VERSION 5.8 ;
BUSBITCHARS "[]" ;
DIVIDERCHAR "/" ;
UNITS
    DATABASE MICRONS 1000 ;
END UNITS

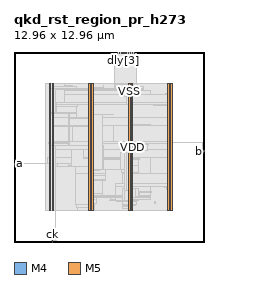
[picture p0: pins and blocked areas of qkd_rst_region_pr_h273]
MACRO qkd_rst_region_pr_h273
  FOREIGN qkd_rst_region_pr_h273 0 0 ;
  CLASS BLOCK ;
  SIZE 12.96 BY 12.96 ;
  PIN a
    DIRECTION INPUT ;
    USE SIGNAL ;
    PORT
      LAYER M4 ;
        RECT  0 5.328 0.084 5.352 ;
    END
  END a
  PIN b
    DIRECTION OUTPUT ;
    USE SIGNAL ;
    PORT
      LAYER M4 ;
        RECT  12.876 6.192 12.96 6.216 ;
    END
  END b
  PIN ck
    DIRECTION INPUT ;
    USE SIGNAL ;
    PORT
      LAYER M5 ;
        RECT  2.592 0 2.616 0.084 ;
    END
  END ck
  PIN dly[0]
    DIRECTION INPUT ;
    USE SIGNAL ;
    PORT
      LAYER M5 ;
        RECT  7.056 12.876 7.08 12.96 ;
    END
  END dly[0]
  PIN dly[1]
    DIRECTION INPUT ;
    USE SIGNAL ;
    PORT
      LAYER M5 ;
        RECT  7.2 12.876 7.224 12.96 ;
    END
  END dly[1]
  PIN dly[2]
    DIRECTION INPUT ;
    USE SIGNAL ;
    PORT
      LAYER M5 ;
        RECT  7.344 12.876 7.368 12.96 ;
    END
  END dly[2]
  PIN dly[3]
    DIRECTION INPUT ;
    USE SIGNAL ;
    PORT
      LAYER M5 ;
        RECT  7.488 12.876 7.512 12.96 ;
    END
  END dly[3]
  PIN dly[4]
    DIRECTION INPUT ;
    USE SIGNAL ;
    PORT
      LAYER M5 ;
        RECT  7.632 12.876 7.656 12.96 ;
    END
  END dly[4]
  PIN dly[5]
    DIRECTION INPUT ;
    USE SIGNAL ;
    PORT
      LAYER M5 ;
        RECT  7.776 12.876 7.8 12.96 ;
    END
  END dly[5]
  PIN dly[6]
    DIRECTION INPUT ;
    USE SIGNAL ;
    PORT
      LAYER M5 ;
        RECT  7.92 12.876 7.944 12.96 ;
    END
  END dly[6]
  PIN dly[7]
    DIRECTION INPUT ;
    USE SIGNAL ;
    PORT
      LAYER M5 ;
        RECT  8.064 12.876 8.088 12.96 ;
    END
  END dly[7]
  PIN por_n
    DIRECTION INPUT ;
    USE SIGNAL ;
    PORT
      LAYER M5 ;
        RECT  8.208 12.876 8.232 12.96 ;
    END
  END por_n
  PIN VDD
    DIRECTION INOUT ;
    USE POWER ;
    PORT
      LAYER M5 ;
        RECT  10.692 2.151 10.812 10.809 ;
        RECT  7.992 2.151 8.112 10.809 ;
        RECT  5.292 2.151 5.412 10.809 ;
        RECT  2.592 2.151 2.712 10.809 ;
    END
  END VDD
  PIN VSS
    DIRECTION INOUT ;
    USE GROUND ;
    PORT
      LAYER M5 ;
        RECT  10.5 2.137 10.62 10.823 ;
        RECT  7.8 2.137 7.92 10.823 ;
        RECT  5.1 2.137 5.22 10.823 ;
        RECT  2.4 2.137 2.52 10.823 ;
    END
  END VSS
  OBS
    LAYER RVTN ;
     RECT  2.16 2.16 10.8 2.295 ;
     RECT  2.16 2.565 10.8 2.835 ;
     RECT  2.16 3.105 10.8 3.375 ;
     RECT  2.16 3.645 10.8 3.915 ;
     RECT  2.16 4.185 10.8 4.455 ;
     RECT  2.16 4.725 10.8 4.995 ;
     RECT  2.16 5.265 10.8 5.535 ;
     RECT  2.16 5.805 10.8 6.075 ;
     RECT  2.16 6.345 10.8 6.615 ;
     RECT  2.16 6.885 10.8 7.155 ;
     RECT  2.16 7.425 10.8 7.695 ;
     RECT  2.16 7.965 10.8 8.235 ;
     RECT  2.16 8.505 10.8 8.775 ;
     RECT  2.16 9.045 10.8 9.315 ;
     RECT  2.16 9.585 10.8 9.855 ;
     RECT  2.16 10.125 10.8 10.395 ;
     RECT  2.16 10.665 10.8 10.8 ;
    LAYER RVTP ;
     RECT  2.16 2.295 10.8 2.565 ;
     RECT  2.16 2.835 10.8 3.105 ;
     RECT  2.16 3.375 10.8 3.645 ;
     RECT  2.16 3.915 10.8 4.185 ;
     RECT  2.16 4.455 10.8 4.725 ;
     RECT  2.16 4.995 10.8 5.265 ;
     RECT  2.16 5.535 10.8 5.805 ;
     RECT  2.16 6.075 10.8 6.345 ;
     RECT  2.16 6.615 10.8 6.885 ;
     RECT  2.16 7.155 10.8 7.425 ;
     RECT  2.16 7.695 10.8 7.965 ;
     RECT  2.16 8.235 10.8 8.505 ;
     RECT  2.16 8.775 10.8 9.045 ;
     RECT  2.16 9.315 10.8 9.585 ;
     RECT  2.16 9.855 10.8 10.125 ;
     RECT  2.16 10.395 10.8 10.665 ;
    LAYER M1 ;
     RECT  2.16 2.151 10.8 10.809 ;
    LAYER M2 ;
     RECT  2.16 2.151 10.8 10.809 ;
     RECT  10.8 2.421 10.812 10.539 ;
     RECT  10.812 6.786 12.875 6.804 ;
    LAYER M3 ;
     RECT  5.115 2.143 5.205 2.191 ;
     RECT  7.815 2.143 7.905 2.299 ;
     RECT  4.32 2.191 4.338 2.335 ;
     RECT  5.115 2.191 5.49 2.335 ;
     RECT  2.415 2.143 2.505 2.413 ;
     RECT  7.416 2.299 7.905 2.413 ;
     RECT  10.515 2.143 10.605 2.413 ;
     RECT  7.416 2.413 8.097 2.461 ;
     RECT  7.416 2.461 8.298 2.569 ;
     RECT  4.284 2.335 5.49 2.621 ;
     RECT  4.32 2.621 5.49 2.641 ;
     RECT  7.416 2.569 8.334 2.731 ;
     RECT  9.612 2.641 9.63 2.759 ;
     RECT  7.02 2.731 8.334 2.803 ;
     RECT  6.552 2.803 8.334 2.839 ;
     RECT  6.552 2.839 8.478 2.875 ;
     RECT  4.32 2.641 5.598 3.037 ;
     RECT  6.552 2.875 9.342 3.037 ;
     RECT  4.32 3.037 9.342 3.137 ;
     RECT  4.788 3.137 9.342 3.173 ;
     RECT  4.788 3.173 6.066 3.335 ;
     RECT  10.515 2.413 10.797 3.577 ;
     RECT  10.368 3.577 10.797 3.685 ;
     RECT  6.948 3.173 9.342 3.811 ;
     RECT  10.26 3.685 10.797 3.811 ;
     RECT  6.948 3.811 10.797 3.983 ;
     RECT  5.076 3.335 6.066 4.225 ;
     RECT  5.076 4.225 6.21 4.261 ;
     RECT  5.076 4.261 6.246 4.531 ;
     RECT  7.416 3.983 10.797 4.649 ;
     RECT  4.572 4.531 6.246 4.651 ;
     RECT  7.416 4.649 8.514 4.765 ;
     RECT  4.356 4.651 6.246 4.955 ;
     RECT  2.415 2.413 2.697 5.131 ;
     RECT  4.356 4.955 4.374 5.165 ;
     RECT  5.115 4.955 6.246 5.233 ;
     RECT  7.308 4.765 8.514 5.233 ;
     RECT  2.415 5.131 2.97 5.323 ;
     RECT  2.304 5.323 2.97 5.341 ;
     RECT  3.744 5.197 3.942 5.341 ;
     RECT  5.115 5.233 8.514 5.611 ;
     RECT  5.115 5.611 8.586 5.701 ;
     RECT  2.304 5.341 3.942 5.765 ;
     RECT  4.716 5.701 8.586 5.773 ;
     RECT  9.324 4.649 10.797 5.773 ;
     RECT  2.415 5.765 3.942 6.313 ;
     RECT  4.716 5.773 10.797 6.313 ;
     RECT  2.415 6.313 10.797 6.691 ;
     RECT  2.376 6.691 10.797 6.749 ;
     RECT  2.376 6.749 4.158 6.809 ;
     RECT  12.852 6.187 12.87 6.809 ;
     RECT  2.415 6.809 4.158 6.845 ;
     RECT  4.932 6.749 10.797 6.845 ;
     RECT  4.932 6.845 6.03 6.881 ;
     RECT  2.415 6.845 3.978 7.861 ;
     RECT  5.115 6.881 6.03 7.861 ;
     RECT  2.415 7.861 6.03 7.933 ;
     RECT  6.768 6.845 10.797 7.933 ;
     RECT  2.415 7.933 10.797 8.501 ;
     RECT  2.415 8.501 4.266 8.779 ;
     RECT  2.412 8.779 4.266 8.843 ;
     RECT  2.415 8.843 4.266 9.247 ;
     RECT  2.415 9.247 4.338 9.355 ;
     RECT  5.115 8.501 10.797 9.355 ;
     RECT  2.415 9.355 10.797 9.509 ;
     RECT  3.42 9.509 10.797 10.049 ;
     RECT  3.42 10.049 9.378 10.085 ;
     RECT  10.224 10.049 10.797 10.085 ;
     RECT  10.332 10.085 10.797 10.121 ;
     RECT  3.42 10.085 9.306 10.319 ;
     RECT  2.415 9.509 2.697 10.411 ;
     RECT  3.42 10.319 8.802 10.411 ;
     RECT  2.415 10.411 8.802 10.463 ;
     RECT  5.115 10.463 6.102 10.547 ;
     RECT  10.515 10.121 10.797 10.547 ;
     RECT  2.415 10.463 4.23 10.589 ;
     RECT  6.84 10.463 8.802 10.589 ;
     RECT  2.415 10.589 4.014 10.625 ;
     RECT  3.42 10.625 4.014 10.661 ;
     RECT  6.084 10.547 6.102 10.661 ;
     RECT  3.42 10.661 3.438 10.769 ;
     RECT  6.84 10.589 6.858 10.781 ;
     RECT  7.632 10.589 8.37 10.781 ;
     RECT  2.415 10.625 2.505 10.817 ;
     RECT  5.115 10.547 5.205 10.817 ;
     RECT  7.815 10.781 8.37 10.817 ;
     RECT  10.515 10.547 10.605 10.817 ;
     RECT  8.352 10.817 8.37 10.829 ;
    LAYER M4 ;
     RECT  0.06 5.328 2.408 5.352 ;
     RECT  2.401 8.784 2.408 8.808 ;
     RECT  2.408 2.148 2.512 10.812 ;
     RECT  2.512 2.418 2.704 10.542 ;
     RECT  2.581 0.096 2.867 0.12 ;
     RECT  2.704 8.784 2.867 9.432 ;
     RECT  2.704 10.416 3.089 10.44 ;
     RECT  2.867 8.784 3.692 8.808 ;
     RECT  2.704 6.576 3.697 6.696 ;
     RECT  3.697 6.576 3.733 6.744 ;
     RECT  3.692 8.16 3.779 8.808 ;
     RECT  2.704 5.136 4.165 5.16 ;
     RECT  4.165 2.592 4.885 2.616 ;
     RECT  4.885 2.592 5.108 2.808 ;
     RECT  4.165 4.656 5.108 5.16 ;
     RECT  3.733 6.576 5.108 6.84 ;
     RECT  3.779 8.4 5.108 8.424 ;
     RECT  5.108 2.148 5.212 10.812 ;
     RECT  5.212 2.418 5.404 10.542 ;
     RECT  5.404 2.88 5.465 2.904 ;
     RECT  5.404 4.848 5.753 6.6 ;
     RECT  5.404 10.416 5.789 10.44 ;
     RECT  5.753 4.848 5.861 6.552 ;
     RECT  5.404 8.496 6.035 8.712 ;
     RECT  5.861 4.944 6.113 6.552 ;
     RECT  6.035 8.688 6.761 8.712 ;
     RECT  6.853 12.816 6.901 12.84 ;
     RECT  6.541 2.832 6.937 2.856 ;
     RECT  6.901 12.672 7.091 12.84 ;
     RECT  6.113 4.944 7.297 5.64 ;
     RECT  6.937 2.832 7.405 3.048 ;
     RECT  6.829 10.464 7.477 10.776 ;
     RECT  7.477 10.224 7.484 10.776 ;
     RECT  7.405 2.832 7.549 3.624 ;
     RECT  7.297 4.944 7.549 6.072 ;
     RECT  7.484 9.936 7.669 10.776 ;
     RECT  7.091 12.672 7.669 12.792 ;
     RECT  7.549 2.832 7.765 6.072 ;
     RECT  7.765 2.784 7.808 6.072 ;
     RECT  7.669 9.36 7.808 10.776 ;
     RECT  7.808 2.148 7.912 10.812 ;
     RECT  7.669 12.576 7.955 12.792 ;
     RECT  7.912 2.418 8.104 10.812 ;
     RECT  7.955 12.672 8.197 12.792 ;
     RECT  8.197 12.672 8.243 12.84 ;
     RECT  8.104 3.024 8.309 3.624 ;
     RECT  8.104 10.032 8.341 10.812 ;
     RECT  8.243 12.816 8.387 12.84 ;
     RECT  8.341 10.032 8.425 10.824 ;
     RECT  8.309 3.072 8.489 3.624 ;
     RECT  8.489 3.072 8.561 3.432 ;
     RECT  8.104 6.24 9.137 6.648 ;
     RECT  9.137 6.624 9.173 6.648 ;
     RECT  8.104 7.968 9.317 7.992 ;
     RECT  8.561 3.408 9.353 3.432 ;
     RECT  8.425 10.032 9.389 10.056 ;
     RECT  9.493 9.312 10.508 9.336 ;
     RECT  10.508 2.148 10.612 10.812 ;
     RECT  10.612 2.418 10.804 10.542 ;
     RECT  12.841 6.192 12.924 6.216 ;
    LAYER M5 ;
     RECT  2.592 0.016 2.616 0.085 ;
     RECT  2.592 0.085 2.856 0.131 ;
     RECT  2.832 0.131 2.856 2.137 ;
     RECT  5.1 2.137 5.22 2.151 ;
     RECT  7.8 2.137 7.92 2.151 ;
     RECT  10.5 2.137 10.62 2.151 ;
     RECT  5.1 2.151 5.412 2.581 ;
     RECT  7.8 2.151 8.112 2.821 ;
     RECT  7.536 2.821 8.112 3.539 ;
     RECT  4.176 2.581 5.412 4.691 ;
     RECT  5.1 4.691 5.412 4.933 ;
     RECT  7.68 3.539 8.112 6.083 ;
     RECT  2.4 2.137 2.856 6.611 ;
     RECT  5.1 4.933 6.024 8.723 ;
     RECT  2.4 6.611 2.712 8.773 ;
     RECT  3.744 6.661 3.768 8.773 ;
     RECT  2.4 8.773 3.768 8.819 ;
     RECT  7.8 6.083 8.112 9.349 ;
     RECT  7.68 9.349 8.112 9.925 ;
     RECT  7.536 9.925 8.112 10.213 ;
     RECT  2.4 8.819 2.856 10.451 ;
     RECT  7.488 10.213 8.112 10.453 ;
     RECT  6.912 10.453 8.112 10.741 ;
     RECT  6.864 10.741 8.232 10.789 ;
     RECT  2.4 10.451 2.712 10.809 ;
     RECT  5.1 8.723 5.412 10.809 ;
     RECT  10.5 2.151 10.812 10.809 ;
     RECT  2.4 10.809 2.52 10.823 ;
     RECT  5.1 10.809 5.22 10.823 ;
     RECT  10.5 10.809 10.62 10.823 ;
     RECT  6.864 10.789 8.376 12.851 ;
     RECT  7.056 12.851 8.232 12.944 ;
  END
END qkd_rst_region_pr_h273
END LIBRARY
